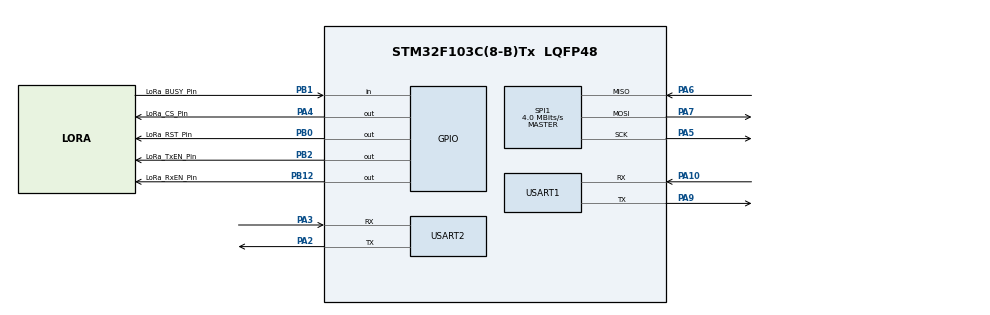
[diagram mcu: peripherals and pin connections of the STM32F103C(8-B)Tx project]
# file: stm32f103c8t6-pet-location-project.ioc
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Mcu.Family=STM32F1
Mcu.Name=STM32F103C(8-B)Tx
Mcu.Package=LQFP48
NVIC.PriorityGroup=NVIC_PRIORITYGROUP_4
PA10.Mode=Asynchronous
PA10.Signal=USART1_RX
PA2.Mode=Asynchronous
PA2.Signal=USART2_TX
PA3.Mode=Asynchronous
PA3.Signal=USART2_RX
PA4.GPIO_Label=LoRa_CS_Pin
PA4.Signal=GPIO_Output
PA5.Mode=Full_Duplex_Master
PA5.Signal=SPI1_SCK
PA6.Mode=Full_Duplex_Master
PA6.Signal=SPI1_MISO
PA7.Mode=Full_Duplex_Master
PA7.Signal=SPI1_MOSI
PA9.Mode=Asynchronous
PA9.Signal=USART1_TX
PB0.GPIO_Label=LoRa_RST_Pin
PB0.Signal=GPIO_Output
PB1.GPIO_Label=LoRa_BUSY_Pin
PB1.Signal=GPIO_Input
PB12.GPIO_Label=LoRa_RxEN_Pin
PB12.Signal=GPIO_Output
PB2.GPIO_Label=LoRa_TxEN_Pin
PB2.Signal=GPIO_Output
ProjectManager.HeapSize=0x200
ProjectManager.StackSize=0x400
ProjectManager.TargetToolchain=STM32CubeIDE
RCC.APB1Freq_Value=8000000
RCC.APB2Freq_Value=8000000
SPI1.CalculateBaudRate=4.0 MBits/s
SPI1.Direction=SPI_DIRECTION_2LINES
SPI1.Mode=SPI_MODE_MASTER
SPI1.VirtualType=VM_MASTER
USART1.VirtualMode=VM_ASYNC
USART2.VirtualMode=VM_ASYNC
VP_SYS_VS_ND.Mode=No_Debug
board=custom

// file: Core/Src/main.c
/* USER CODE BEGIN Header */
/**
  ******************************************************************************
  * @file           : main.c
  * @brief          : Main program body
  ******************************************************************************
  * @attention
  *
  * Copyright (c) 2024 STMicroelectronics.
  * All rights reserved.
  *
  * This software is licensed under terms that can be found in the LICENSE file
  * in the root directory of this software component.
  * If no LICENSE file comes with this software, it is provided AS-IS.
  *
  ******************************************************************************
  */
/* USER CODE END Header */
#include "main.h"
#include "LoRa.h"
#include "stdio.h"
#include "socket.h"
#include "gps.h"

#include "string.h"

SPI_HandleTypeDef hspi1;

UART_HandleTypeDef huart1;
UART_HandleTypeDef huart2;

uint8_t __io_putchar(int ch) {
    uint8_t temp[1] = {ch};
    HAL_UART_Transmit(&huart1, temp, 1, 2);
    return (ch);
}

uint8_t _write(int file, char *ptr, int len) {
    int DataIdx;
    for (DataIdx = 0; DataIdx < len; DataIdx++) {
        __io_putchar(*ptr++);
    }
    return len;
}

void SystemClock_Config(void);

static void MX_GPIO_Init(void);

static void MX_SPI1_Init(void);

static void MX_USART1_UART_Init(void);

static void MX_USART2_UART_Init(void);

/* USER CODE BEGIN PFP */

uint8_t msg[100] = {0};

/* USER CODE END PFP */

int main(void) {

    /* MCU Configuration--------------------------------------------------------*/

    /* Reset of all peripherals, Initializes the Flash interface and the Systick. */
    HAL_Init();

    /* Configure the system clock */
    SystemClock_Config();

    /* Initialize all configured peripherals */
    MX_GPIO_Init();
    MX_SPI1_Init();
    MX_USART1_UART_Init();
    MX_USART2_UART_Init();
    /* USER CODE BEGIN 2 */

    printf("hello world\r\n");

    LoRa_Init();
    uint32_t name = Ebyte_RF.GetName();
    printf("LoRa设备名称=0x%x\r\n", name);

    socket_at_test();
    socket_at_csq();

    gps_cold_start();
    HAL_Delay(1000);
    gps_enable();
    HAL_Delay(1000);
    gps_location();

    socket_at_enable();
    socket_at_set_params();
    socket_disable_ssl();
    HAL_UART_Transmit(&huart2, "adminAT+S\r\n", 11, HAL_MAX_DELAY);

//    socket_at_enable();

//    socket_at_query_params();
//    socket_at_max_connection();
//    socket_at_set_socket_type();
    HAL_Delay(5000);

//    socket_exit_config_mode();

    /* USER CODE END 2 */

    /* Infinite loop */
    while (1) {
//        LoRa_StartPollTask();
//        memset(msg, 0, sizeof((char *) msg));
//        /* 给 LoRa 网关发送数据 */
//        sprintf((char *) msg, "hello zhenchao...");
//        LoRa_Send(msg, strlen((char *) msg));
//        HAL_UART_Transmit(&huart2, "hello world\r\n", 13, HAL_MAX_DELAY);
        socket_at_creg();
        HAL_Delay(1000);
        socket_at_query_connect_state();

//        HAL_UART_Transmit(&huart2, "adminAT+ENTM\r\n", 14, HAL_MAX_DELAY);

//        HAL_UART_Transmit(&huart2, "hello world\r\n", 13, HAL_MAX_DELAY);

//        HAL_UART_Transmit(&huart2, "xxx\r\n", 5, HAL_MAX_DELAY);

        gps_location();

        HAL_Delay(10000);

    }
}

void SystemClock_Config(void) {
    RCC_OscInitTypeDef RCC_OscInitStruct = {0};
    RCC_ClkInitTypeDef RCC_ClkInitStruct = {0};

    /** Initializes the RCC Oscillators according to the specified parameters
    * in the RCC_OscInitTypeDef structure.
    */
    RCC_OscInitStruct.OscillatorType = RCC_OSCILLATORTYPE_HSI;
    RCC_OscInitStruct.HSIState = RCC_HSI_ON;
    RCC_OscInitStruct.HSICalibrationValue = RCC_HSICALIBRATION_DEFAULT;
    RCC_OscInitStruct.PLL.PLLState = RCC_PLL_NONE;
    if (HAL_RCC_OscConfig(&RCC_OscInitStruct) != HAL_OK) {
        Error_Handler();
    }

    /** Initializes the CPU, AHB and APB buses clocks
    */
    RCC_ClkInitStruct.ClockType = RCC_CLOCKTYPE_HCLK | RCC_CLOCKTYPE_SYSCLK
                                  | RCC_CLOCKTYPE_PCLK1 | RCC_CLOCKTYPE_PCLK2;
    RCC_ClkInitStruct.SYSCLKSource = RCC_SYSCLKSOURCE_HSI;
    RCC_ClkInitStruct.AHBCLKDivider = RCC_SYSCLK_DIV1;
    RCC_ClkInitStruct.APB1CLKDivider = RCC_HCLK_DIV1;
    RCC_ClkInitStruct.APB2CLKDivider = RCC_HCLK_DIV1;

    if (HAL_RCC_ClockConfig(&RCC_ClkInitStruct, FLASH_LATENCY_0) != HAL_OK) {
        Error_Handler();
    }
}

static void MX_SPI1_Init(void) {

    /* SPI1 parameter configuration*/
    hspi1.Instance = SPI1;
    hspi1.Init.Mode = SPI_MODE_MASTER;
    hspi1.Init.Direction = SPI_DIRECTION_2LINES;
    hspi1.Init.DataSize = SPI_DATASIZE_8BIT;
    hspi1.Init.CLKPolarity = SPI_POLARITY_LOW;
    hspi1.Init.CLKPhase = SPI_PHASE_1EDGE;
    hspi1.Init.NSS = SPI_NSS_SOFT;
    hspi1.Init.BaudRatePrescaler = SPI_BAUDRATEPRESCALER_2;
    hspi1.Init.FirstBit = SPI_FIRSTBIT_MSB;
    hspi1.Init.TIMode = SPI_TIMODE_DISABLE;
    hspi1.Init.CRCCalculation = SPI_CRCCALCULATION_DISABLE;
    hspi1.Init.CRCPolynomial = 10;
    if (HAL_SPI_Init(&hspi1) != HAL_OK) {
        Error_Handler();
    }

}

static void MX_USART1_UART_Init(void) {

    huart1.Instance = USART1;
    huart1.Init.BaudRate = 115200;
    huart1.Init.WordLength = UART_WORDLENGTH_8B;
    huart1.Init.StopBits = UART_STOPBITS_1;
    huart1.Init.Parity = UART_PARITY_NONE;
    huart1.Init.Mode = UART_MODE_TX_RX;
    huart1.Init.HwFlowCtl = UART_HWCONTROL_NONE;
    huart1.Init.OverSampling = UART_OVERSAMPLING_16;
    if (HAL_UART_Init(&huart1) != HAL_OK) {
        Error_Handler();
    }

}

static void MX_USART2_UART_Init(void) {

    huart2.Instance = USART2;
    huart2.Init.BaudRate = 115200;
    huart2.Init.WordLength = UART_WORDLENGTH_8B;
    huart2.Init.StopBits = UART_STOPBITS_1;
    huart2.Init.Parity = UART_PARITY_NONE;
    huart2.Init.Mode = UART_MODE_TX_RX;
    huart2.Init.HwFlowCtl = UART_HWCONTROL_NONE;
    huart2.Init.OverSampling = UART_OVERSAMPLING_16;
    if (HAL_UART_Init(&huart2) != HAL_OK) {
        Error_Handler();
    }

}

static void MX_GPIO_Init(void) {
    GPIO_InitTypeDef GPIO_InitStruct = {0};

    /* GPIO Ports Clock Enable */
    __HAL_RCC_GPIOA_CLK_ENABLE();
    __HAL_RCC_GPIOB_CLK_ENABLE();

    /*Configure GPIO pin Output Level */
    HAL_GPIO_WritePin(LoRa_CS_GPIO_Port, LoRa_CS_Pin, GPIO_PIN_RESET);

    /*Configure GPIO pin Output Level */
    HAL_GPIO_WritePin(GPIOB, LoRa_RST_Pin | LoRa_TxEN_Pin | LoRa_RxEN_Pin, GPIO_PIN_RESET);

    /*Configure GPIO pin : LoRa_CS_Pin_Pin */
    GPIO_InitStruct.Pin = LoRa_CS_Pin;
    GPIO_InitStruct.Mode = GPIO_MODE_OUTPUT_PP;
    GPIO_InitStruct.Pull = GPIO_NOPULL;
    GPIO_InitStruct.Speed = GPIO_SPEED_FREQ_LOW;
    HAL_GPIO_Init(LoRa_CS_GPIO_Port, &GPIO_InitStruct);

    /*Configure GPIO pins : LoRa_RST_Pin_Pin LoRa_TxEN_Pin_Pin LoRa_RxEN_Pin_Pin */
    GPIO_InitStruct.Pin = LoRa_RST_Pin | LoRa_TxEN_Pin | LoRa_RxEN_Pin;
    GPIO_InitStruct.Mode = GPIO_MODE_OUTPUT_PP;
    GPIO_InitStruct.Pull = GPIO_NOPULL;
    GPIO_InitStruct.Speed = GPIO_SPEED_FREQ_LOW;
    HAL_GPIO_Init(GPIOB, &GPIO_InitStruct);

    /*Configure GPIO pin : LoRa_BUSY_Pin_Pin */
    GPIO_InitStruct.Pin = LoRa_BUSY_Pin;
    GPIO_InitStruct.Mode = GPIO_MODE_INPUT;
    GPIO_InitStruct.Pull = GPIO_NOPULL;
    HAL_GPIO_Init(LoRa_BUSY_GPIO_Port, &GPIO_InitStruct);

}

void Error_Handler(void) {
    __disable_irq();
    while (1) {
    }
}
